One B-rep face of a CAD part: STEP entity #140.
In plain terms, the planar face has unit normal (0, 0, 1).
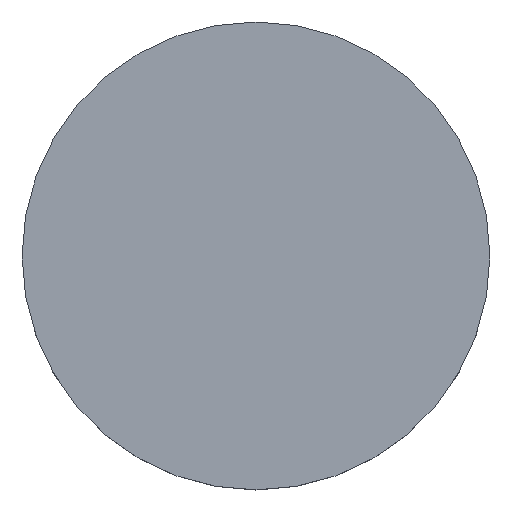
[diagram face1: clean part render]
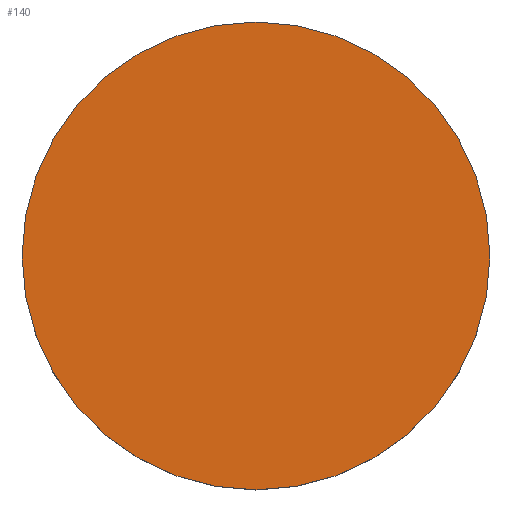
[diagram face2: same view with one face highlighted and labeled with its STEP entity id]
Its self-contained STEP definition (entity closure, numbers rounded to 3 decimals):
#24 = VERTEX_POINT('',#25);
#25 = CARTESIAN_POINT('',(1.9,0.,4.55));
#32 = CYLINDRICAL_SURFACE('',#33,1.9);
#33 = AXIS2_PLACEMENT_3D('',#34,#35,#36);
#34 = CARTESIAN_POINT('',(0.,0.,4.));
#35 = DIRECTION('',(-0.,-0.,-1.));
#36 = DIRECTION('',(1.,0.,0.));
#51 = EDGE_CURVE('',#24,#24,#52,.T.);
#52 = SURFACE_CURVE('',#53,(#58,#65),.PCURVE_S1.);
#53 = CIRCLE('',#54,1.9);
#54 = AXIS2_PLACEMENT_3D('',#55,#56,#57);
#55 = CARTESIAN_POINT('',(0.,0.,4.55));
#56 = DIRECTION('',(0.,0.,1.));
#57 = DIRECTION('',(1.,0.,0.));
#58 = PCURVE('',#32,#59);
#59 = DEFINITIONAL_REPRESENTATION('',(#60),#64);
#60 = LINE('',#61,#62);
#61 = CARTESIAN_POINT('',(-0.,-0.55));
#62 = VECTOR('',#63,1.);
#63 = DIRECTION('',(-1.,0.));
#64 = ( GEOMETRIC_REPRESENTATION_CONTEXT(2) 
PARAMETRIC_REPRESENTATION_CONTEXT() REPRESENTATION_CONTEXT('2D SPACE',''
  ) );
#65 = PCURVE('',#66,#71);
#66 = PLANE('',#67);
#67 = AXIS2_PLACEMENT_3D('',#68,#69,#70);
#68 = CARTESIAN_POINT('',(0.,0.,4.55));
#69 = DIRECTION('',(0.,0.,1.));
#70 = DIRECTION('',(1.,0.,-0.));
#71 = DEFINITIONAL_REPRESENTATION('',(#72),#76);
#72 = CIRCLE('',#73,1.9);
#73 = AXIS2_PLACEMENT_2D('',#74,#75);
#74 = CARTESIAN_POINT('',(0.,0.));
#75 = DIRECTION('',(1.,0.));
#76 = ( GEOMETRIC_REPRESENTATION_CONTEXT(2) 
PARAMETRIC_REPRESENTATION_CONTEXT() REPRESENTATION_CONTEXT('2D SPACE',''
  ) );
#140 = ADVANCED_FACE('',(#141),#66,.T.);
#141 = FACE_BOUND('',#142,.T.);
#142 = EDGE_LOOP('',(#143));
#143 = ORIENTED_EDGE('',*,*,#51,.T.);
